VERSION 5.7 ;
NOWIREEXTENSIONATPIN ON ;
DIVIDERCHAR "/" ;
BUSBITCHARS "[]" ;

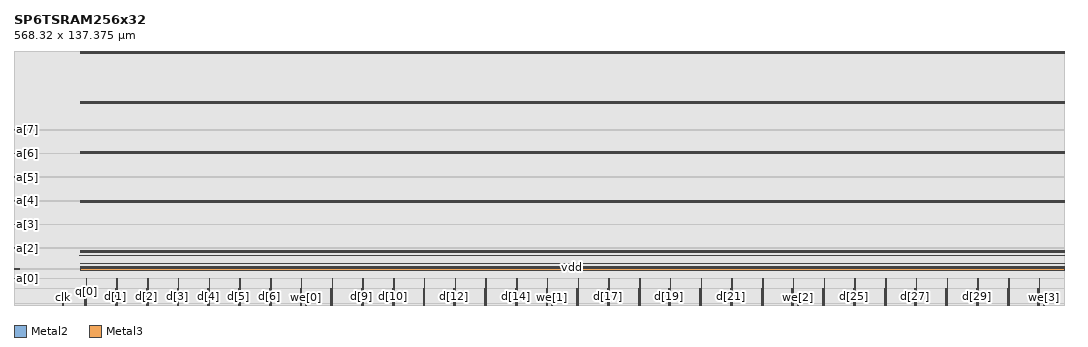
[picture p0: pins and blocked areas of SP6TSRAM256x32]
MACRO SP6TSRAM256x32
  CLASS BLOCK ;
  FOREIGN SP6TSRAM256x32 ;
  ORIGIN 0.000 0.000 ;
  SIZE 568.320 BY 137.375 ;
  SYMMETRY X Y R90 ;
  PIN clk
    USE CLOCK ;
    DIRECTION INPUT ;
    PORT
      LAYER Metal2 ;
        RECT 26.175 0.000 26.555 1.900 ;
    END
  END clk
  PIN a[0]
    USE SIGNAL ;
    DIRECTION INPUT ;
    PORT
      LAYER Metal3 ;
        RECT 0.000 14.185 2.980 14.465 ;
    END
  END a[0]
  PIN a[1]
    USE SIGNAL ;
    DIRECTION INPUT ;
    PORT
      LAYER Metal3 ;
        RECT 0.000 19.485 2.980 19.765 ;
    END
  END a[1]
  PIN a[2]
    USE SIGNAL ;
    DIRECTION INPUT ;
    PORT
      LAYER Metal3 ;
        RECT 0.000 30.685 2.510 30.965 ;
    END
  END a[2]
  PIN a[3]
    USE SIGNAL ;
    DIRECTION INPUT ;
    PORT
      LAYER Metal3 ;
        RECT 0.000 43.485 2.510 43.765 ;
    END
  END a[3]
  PIN a[4]
    USE SIGNAL ;
    DIRECTION INPUT ;
    PORT
      LAYER Metal3 ;
        RECT 0.000 56.285 2.510 56.565 ;
    END
  END a[4]
  PIN a[5]
    USE SIGNAL ;
    DIRECTION INPUT ;
    PORT
      LAYER Metal3 ;
        RECT 0.000 69.085 2.510 69.365 ;
    END
  END a[5]
  PIN a[6]
    USE SIGNAL ;
    DIRECTION INPUT ;
    PORT
      LAYER Metal3 ;
        RECT 0.000 81.885 2.510 82.165 ;
    END
  END a[6]
  PIN a[7]
    USE SIGNAL ;
    DIRECTION INPUT ;
    PORT
      LAYER Metal3 ;
        RECT 0.000 94.685 2.510 94.965 ;
    END
  END a[7]
  PIN d[0]
    USE SIGNAL ;
    DIRECTION INPUT ;
    PORT
      LAYER Metal3 ;
        RECT 38.350 0.000 38.630 9.140 ;
    END
  END d[0]
  PIN d[1]
    USE SIGNAL ;
    DIRECTION INPUT ;
    PORT
      LAYER Metal3 ;
        RECT 54.990 0.000 55.270 9.140 ;
    END
  END d[1]
  PIN d[2]
    USE SIGNAL ;
    DIRECTION INPUT ;
    PORT
      LAYER Metal3 ;
        RECT 71.630 0.000 71.910 9.140 ;
    END
  END d[2]
  PIN d[3]
    USE SIGNAL ;
    DIRECTION INPUT ;
    PORT
      LAYER Metal3 ;
        RECT 88.270 0.000 88.550 9.140 ;
    END
  END d[3]
  PIN d[4]
    USE SIGNAL ;
    DIRECTION INPUT ;
    PORT
      LAYER Metal3 ;
        RECT 104.910 0.000 105.190 9.140 ;
    END
  END d[4]
  PIN d[5]
    USE SIGNAL ;
    DIRECTION INPUT ;
    PORT
      LAYER Metal3 ;
        RECT 121.550 0.000 121.830 9.140 ;
    END
  END d[5]
  PIN d[6]
    USE SIGNAL ;
    DIRECTION INPUT ;
    PORT
      LAYER Metal3 ;
        RECT 138.190 0.000 138.470 9.140 ;
    END
  END d[6]
  PIN d[7]
    USE SIGNAL ;
    DIRECTION INPUT ;
    PORT
      LAYER Metal3 ;
        RECT 154.830 0.000 155.110 9.140 ;
    END
  END d[7]
  PIN d[8]
    USE SIGNAL ;
    DIRECTION INPUT ;
    PORT
      LAYER Metal3 ;
        RECT 171.470 0.000 171.750 9.140 ;
    END
  END d[8]
  PIN d[9]
    USE SIGNAL ;
    DIRECTION INPUT ;
    PORT
      LAYER Metal3 ;
        RECT 188.110 0.000 188.390 9.140 ;
    END
  END d[9]
  PIN d[10]
    USE SIGNAL ;
    DIRECTION INPUT ;
    PORT
      LAYER Metal3 ;
        RECT 204.750 0.000 205.030 9.140 ;
    END
  END d[10]
  PIN d[11]
    USE SIGNAL ;
    DIRECTION INPUT ;
    PORT
      LAYER Metal3 ;
        RECT 221.390 0.000 221.670 9.140 ;
    END
  END d[11]
  PIN d[12]
    USE SIGNAL ;
    DIRECTION INPUT ;
    PORT
      LAYER Metal3 ;
        RECT 238.030 0.000 238.310 9.140 ;
    END
  END d[12]
  PIN d[13]
    USE SIGNAL ;
    DIRECTION INPUT ;
    PORT
      LAYER Metal3 ;
        RECT 254.670 0.000 254.950 9.140 ;
    END
  END d[13]
  PIN d[14]
    USE SIGNAL ;
    DIRECTION INPUT ;
    PORT
      LAYER Metal3 ;
        RECT 271.310 0.000 271.590 9.140 ;
    END
  END d[14]
  PIN d[15]
    USE SIGNAL ;
    DIRECTION INPUT ;
    PORT
      LAYER Metal3 ;
        RECT 287.950 0.000 288.230 9.140 ;
    END
  END d[15]
  PIN d[16]
    USE SIGNAL ;
    DIRECTION INPUT ;
    PORT
      LAYER Metal3 ;
        RECT 304.590 0.000 304.870 9.140 ;
    END
  END d[16]
  PIN d[17]
    USE SIGNAL ;
    DIRECTION INPUT ;
    PORT
      LAYER Metal3 ;
        RECT 321.230 0.000 321.510 9.140 ;
    END
  END d[17]
  PIN d[18]
    USE SIGNAL ;
    DIRECTION INPUT ;
    PORT
      LAYER Metal3 ;
        RECT 337.870 0.000 338.150 9.140 ;
    END
  END d[18]
  PIN d[19]
    USE SIGNAL ;
    DIRECTION INPUT ;
    PORT
      LAYER Metal3 ;
        RECT 354.510 0.000 354.790 9.140 ;
    END
  END d[19]
  PIN d[20]
    USE SIGNAL ;
    DIRECTION INPUT ;
    PORT
      LAYER Metal3 ;
        RECT 371.150 0.000 371.430 9.140 ;
    END
  END d[20]
  PIN d[21]
    USE SIGNAL ;
    DIRECTION INPUT ;
    PORT
      LAYER Metal3 ;
        RECT 387.790 0.000 388.070 9.140 ;
    END
  END d[21]
  PIN d[22]
    USE SIGNAL ;
    DIRECTION INPUT ;
    PORT
      LAYER Metal3 ;
        RECT 404.430 0.000 404.710 9.140 ;
    END
  END d[22]
  PIN d[23]
    USE SIGNAL ;
    DIRECTION INPUT ;
    PORT
      LAYER Metal3 ;
        RECT 421.070 0.000 421.350 9.140 ;
    END
  END d[23]
  PIN d[24]
    USE SIGNAL ;
    DIRECTION INPUT ;
    PORT
      LAYER Metal3 ;
        RECT 437.710 0.000 437.990 9.140 ;
    END
  END d[24]
  PIN d[25]
    USE SIGNAL ;
    DIRECTION INPUT ;
    PORT
      LAYER Metal3 ;
        RECT 454.350 0.000 454.630 9.140 ;
    END
  END d[25]
  PIN d[26]
    USE SIGNAL ;
    DIRECTION INPUT ;
    PORT
      LAYER Metal3 ;
        RECT 470.990 0.000 471.270 9.140 ;
    END
  END d[26]
  PIN d[27]
    USE SIGNAL ;
    DIRECTION INPUT ;
    PORT
      LAYER Metal3 ;
        RECT 487.630 0.000 487.910 9.140 ;
    END
  END d[27]
  PIN d[28]
    USE SIGNAL ;
    DIRECTION INPUT ;
    PORT
      LAYER Metal3 ;
        RECT 504.270 0.000 504.550 9.140 ;
    END
  END d[28]
  PIN d[29]
    USE SIGNAL ;
    DIRECTION INPUT ;
    PORT
      LAYER Metal3 ;
        RECT 520.910 0.000 521.190 9.140 ;
    END
  END d[29]
  PIN d[30]
    USE SIGNAL ;
    DIRECTION INPUT ;
    PORT
      LAYER Metal3 ;
        RECT 537.550 0.000 537.830 9.140 ;
    END
  END d[30]
  PIN d[31]
    USE SIGNAL ;
    DIRECTION INPUT ;
    PORT
      LAYER Metal3 ;
        RECT 554.190 0.000 554.470 9.140 ;
    END
  END d[31]
  PIN we[0]
    USE SIGNAL ;
    DIRECTION INPUT ;
    PORT
      LAYER Metal3 ;
        RECT 157.870 0.000 158.150 1.000 ;
    END
  END we[0]
  PIN we[1]
    USE SIGNAL ;
    DIRECTION INPUT ;
    PORT
      LAYER Metal3 ;
        RECT 290.990 0.000 291.270 1.000 ;
    END
  END we[1]
  PIN we[2]
    USE SIGNAL ;
    DIRECTION INPUT ;
    PORT
      LAYER Metal3 ;
        RECT 424.110 0.000 424.390 1.000 ;
    END
  END we[2]
  PIN we[3]
    USE SIGNAL ;
    DIRECTION INPUT ;
    PORT
      LAYER Metal3 ;
        RECT 557.230 0.000 557.510 1.000 ;
    END
  END we[3]
  PIN q[0]
    USE SIGNAL ;
    DIRECTION OUTPUT ;
    PORT
      LAYER Metal3 ;
        RECT 39.090 0.000 39.370 14.190 ;
    END
  END q[0]
  PIN q[1]
    USE SIGNAL ;
    DIRECTION OUTPUT ;
    PORT
      LAYER Metal3 ;
        RECT 55.730 0.000 56.010 14.190 ;
    END
  END q[1]
  PIN q[2]
    USE SIGNAL ;
    DIRECTION OUTPUT ;
    PORT
      LAYER Metal3 ;
        RECT 72.370 0.000 72.650 14.190 ;
    END
  END q[2]
  PIN q[3]
    USE SIGNAL ;
    DIRECTION OUTPUT ;
    PORT
      LAYER Metal3 ;
        RECT 89.010 0.000 89.290 14.190 ;
    END
  END q[3]
  PIN q[4]
    USE SIGNAL ;
    DIRECTION OUTPUT ;
    PORT
      LAYER Metal3 ;
        RECT 105.650 0.000 105.930 14.190 ;
    END
  END q[4]
  PIN q[5]
    USE SIGNAL ;
    DIRECTION OUTPUT ;
    PORT
      LAYER Metal3 ;
        RECT 122.290 0.000 122.570 14.190 ;
    END
  END q[5]
  PIN q[6]
    USE SIGNAL ;
    DIRECTION OUTPUT ;
    PORT
      LAYER Metal3 ;
        RECT 138.930 0.000 139.210 14.190 ;
    END
  END q[6]
  PIN q[7]
    USE SIGNAL ;
    DIRECTION OUTPUT ;
    PORT
      LAYER Metal3 ;
        RECT 155.570 0.000 155.850 14.190 ;
    END
  END q[7]
  PIN q[8]
    USE SIGNAL ;
    DIRECTION OUTPUT ;
    PORT
      LAYER Metal3 ;
        RECT 172.210 0.000 172.490 14.190 ;
    END
  END q[8]
  PIN q[9]
    USE SIGNAL ;
    DIRECTION OUTPUT ;
    PORT
      LAYER Metal3 ;
        RECT 188.850 0.000 189.130 14.190 ;
    END
  END q[9]
  PIN q[10]
    USE SIGNAL ;
    DIRECTION OUTPUT ;
    PORT
      LAYER Metal3 ;
        RECT 205.490 0.000 205.770 14.190 ;
    END
  END q[10]
  PIN q[11]
    USE SIGNAL ;
    DIRECTION OUTPUT ;
    PORT
      LAYER Metal3 ;
        RECT 222.130 0.000 222.410 14.190 ;
    END
  END q[11]
  PIN q[12]
    USE SIGNAL ;
    DIRECTION OUTPUT ;
    PORT
      LAYER Metal3 ;
        RECT 238.770 0.000 239.050 14.190 ;
    END
  END q[12]
  PIN q[13]
    USE SIGNAL ;
    DIRECTION OUTPUT ;
    PORT
      LAYER Metal3 ;
        RECT 255.410 0.000 255.690 14.190 ;
    END
  END q[13]
  PIN q[14]
    USE SIGNAL ;
    DIRECTION OUTPUT ;
    PORT
      LAYER Metal3 ;
        RECT 272.050 0.000 272.330 14.190 ;
    END
  END q[14]
  PIN q[15]
    USE SIGNAL ;
    DIRECTION OUTPUT ;
    PORT
      LAYER Metal3 ;
        RECT 288.690 0.000 288.970 14.190 ;
    END
  END q[15]
  PIN q[16]
    USE SIGNAL ;
    DIRECTION OUTPUT ;
    PORT
      LAYER Metal3 ;
        RECT 305.330 0.000 305.610 14.190 ;
    END
  END q[16]
  PIN q[17]
    USE SIGNAL ;
    DIRECTION OUTPUT ;
    PORT
      LAYER Metal3 ;
        RECT 321.970 0.000 322.250 14.190 ;
    END
  END q[17]
  PIN q[18]
    USE SIGNAL ;
    DIRECTION OUTPUT ;
    PORT
      LAYER Metal3 ;
        RECT 338.610 0.000 338.890 14.190 ;
    END
  END q[18]
  PIN q[19]
    USE SIGNAL ;
    DIRECTION OUTPUT ;
    PORT
      LAYER Metal3 ;
        RECT 355.250 0.000 355.530 14.190 ;
    END
  END q[19]
  PIN q[20]
    USE SIGNAL ;
    DIRECTION OUTPUT ;
    PORT
      LAYER Metal3 ;
        RECT 371.890 0.000 372.170 14.190 ;
    END
  END q[20]
  PIN q[21]
    USE SIGNAL ;
    DIRECTION OUTPUT ;
    PORT
      LAYER Metal3 ;
        RECT 388.530 0.000 388.810 14.190 ;
    END
  END q[21]
  PIN q[22]
    USE SIGNAL ;
    DIRECTION OUTPUT ;
    PORT
      LAYER Metal3 ;
        RECT 405.170 0.000 405.450 14.190 ;
    END
  END q[22]
  PIN q[23]
    USE SIGNAL ;
    DIRECTION OUTPUT ;
    PORT
      LAYER Metal3 ;
        RECT 421.810 0.000 422.090 14.190 ;
    END
  END q[23]
  PIN q[24]
    USE SIGNAL ;
    DIRECTION OUTPUT ;
    PORT
      LAYER Metal3 ;
        RECT 438.450 0.000 438.730 14.190 ;
    END
  END q[24]
  PIN q[25]
    USE SIGNAL ;
    DIRECTION OUTPUT ;
    PORT
      LAYER Metal3 ;
        RECT 455.090 0.000 455.370 14.190 ;
    END
  END q[25]
  PIN q[26]
    USE SIGNAL ;
    DIRECTION OUTPUT ;
    PORT
      LAYER Metal3 ;
        RECT 471.730 0.000 472.010 14.190 ;
    END
  END q[26]
  PIN q[27]
    USE SIGNAL ;
    DIRECTION OUTPUT ;
    PORT
      LAYER Metal3 ;
        RECT 488.370 0.000 488.650 14.190 ;
    END
  END q[27]
  PIN q[28]
    USE SIGNAL ;
    DIRECTION OUTPUT ;
    PORT
      LAYER Metal3 ;
        RECT 505.010 0.000 505.290 14.190 ;
    END
  END q[28]
  PIN q[29]
    USE SIGNAL ;
    DIRECTION OUTPUT ;
    PORT
      LAYER Metal3 ;
        RECT 521.650 0.000 521.930 14.190 ;
    END
  END q[29]
  PIN q[30]
    USE SIGNAL ;
    DIRECTION OUTPUT ;
    PORT
      LAYER Metal3 ;
        RECT 538.290 0.000 538.570 14.190 ;
    END
  END q[30]
  PIN q[31]
    USE SIGNAL ;
    DIRECTION OUTPUT ;
    PORT
      LAYER Metal3 ;
        RECT 554.930 0.000 555.210 14.190 ;
    END
  END q[31]
  PIN vss
    USE GROUND ;
    DIRECTION INOUT ;
    PORT
      LAYER Metal3 ;
        RECT 35.840 28.315 568.320 28.715 ;
    END
    PORT
      LAYER Metal3 ;
        RECT 35.840 109.195 568.320 109.595 ;
    END
    PORT
      LAYER Metal3 ;
        RECT 35.840 82.235 568.320 82.635 ;
    END
    PORT
      LAYER Metal3 ;
        RECT 35.840 55.275 568.320 55.675 ;
    END
    PORT
      LAYER Metal3 ;
        RECT 35.840 136.155 568.320 136.555 ;
    END
    PORT
      LAYER Metal3 ;
        RECT 35.840 22.450 568.320 22.730 ;
    END
    PORT
      LAYER Metal3 ;
        RECT 35.840 18.780 568.320 19.780 ;
    END
  END vss
  PIN vdd
    USE POWER ;
    DIRECTION INOUT ;
    PORT
      LAYER Metal3 ;
        RECT 35.840 82.915 568.320 83.315 ;
    END
    PORT
      LAYER Metal3 ;
        RECT 35.840 109.875 568.320 110.275 ;
    END
    PORT
      LAYER Metal3 ;
        RECT 35.840 136.835 568.320 137.235 ;
    END
    PORT
      LAYER Metal3 ;
        RECT 35.840 28.995 568.320 29.395 ;
    END
    PORT
      LAYER Metal3 ;
        RECT 35.840 55.955 568.320 56.355 ;
    END
    PORT
      LAYER Metal3 ;
        RECT 35.840 20.060 568.320 21.060 ;
    END
    PORT
      LAYER Metal3 ;
        RECT 35.650 26.745 568.320 27.025 ;
    END
  END vdd
  OBS
    LAYER Metal1 ;
      RECT 0.000 0.000 568.320 137.375 ;
    LAYER Metal2 ;
      RECT 0.000 0.000 26.175 1.900 ;
      RECT 26.555 0.000 568.320 1.900 ;
      RECT 0.000 1.900 568.320 137.375 ;
    LAYER Metal3 ;
      RECT 0.000 0.000 38.350 1.000 ;
      RECT 38.630 0.000 39.090 1.000 ;
      RECT 39.370 0.000 54.990 1.000 ;
      RECT 55.270 0.000 55.730 1.000 ;
      RECT 56.010 0.000 71.630 1.000 ;
      RECT 71.910 0.000 72.370 1.000 ;
      RECT 72.650 0.000 88.270 1.000 ;
      RECT 88.550 0.000 89.010 1.000 ;
      RECT 89.290 0.000 104.910 1.000 ;
      RECT 105.190 0.000 105.650 1.000 ;
      RECT 105.930 0.000 121.550 1.000 ;
      RECT 121.830 0.000 122.290 1.000 ;
      RECT 122.570 0.000 138.190 1.000 ;
      RECT 138.470 0.000 138.930 1.000 ;
      RECT 139.210 0.000 154.830 1.000 ;
      RECT 155.110 0.000 155.570 1.000 ;
      RECT 155.850 0.000 157.870 1.000 ;
      RECT 158.150 0.000 171.470 1.000 ;
      RECT 171.750 0.000 172.210 1.000 ;
      RECT 172.490 0.000 188.110 1.000 ;
      RECT 188.390 0.000 188.850 1.000 ;
      RECT 189.130 0.000 204.750 1.000 ;
      RECT 205.030 0.000 205.490 1.000 ;
      RECT 205.770 0.000 221.390 1.000 ;
      RECT 221.670 0.000 222.130 1.000 ;
      RECT 222.410 0.000 238.030 1.000 ;
      RECT 238.310 0.000 238.770 1.000 ;
      RECT 239.050 0.000 254.670 1.000 ;
      RECT 254.950 0.000 255.410 1.000 ;
      RECT 255.690 0.000 271.310 1.000 ;
      RECT 271.590 0.000 272.050 1.000 ;
      RECT 272.330 0.000 287.950 1.000 ;
      RECT 288.230 0.000 288.690 1.000 ;
      RECT 288.970 0.000 290.990 1.000 ;
      RECT 291.270 0.000 304.590 1.000 ;
      RECT 304.870 0.000 305.330 1.000 ;
      RECT 305.610 0.000 321.230 1.000 ;
      RECT 321.510 0.000 321.970 1.000 ;
      RECT 322.250 0.000 337.870 1.000 ;
      RECT 338.150 0.000 338.610 1.000 ;
      RECT 338.890 0.000 354.510 1.000 ;
      RECT 354.790 0.000 355.250 1.000 ;
      RECT 355.530 0.000 371.150 1.000 ;
      RECT 371.430 0.000 371.890 1.000 ;
      RECT 372.170 0.000 387.790 1.000 ;
      RECT 388.070 0.000 388.530 1.000 ;
      RECT 388.810 0.000 404.430 1.000 ;
      RECT 404.710 0.000 405.170 1.000 ;
      RECT 405.450 0.000 421.070 1.000 ;
      RECT 421.350 0.000 421.810 1.000 ;
      RECT 422.090 0.000 424.110 1.000 ;
      RECT 424.390 0.000 437.710 1.000 ;
      RECT 437.990 0.000 438.450 1.000 ;
      RECT 438.730 0.000 454.350 1.000 ;
      RECT 454.630 0.000 455.090 1.000 ;
      RECT 455.370 0.000 470.990 1.000 ;
      RECT 471.270 0.000 471.730 1.000 ;
      RECT 472.010 0.000 487.630 1.000 ;
      RECT 487.910 0.000 488.370 1.000 ;
      RECT 488.650 0.000 504.270 1.000 ;
      RECT 504.550 0.000 505.010 1.000 ;
      RECT 505.290 0.000 520.910 1.000 ;
      RECT 521.190 0.000 521.650 1.000 ;
      RECT 521.930 0.000 537.550 1.000 ;
      RECT 537.830 0.000 538.290 1.000 ;
      RECT 538.570 0.000 554.190 1.000 ;
      RECT 554.470 0.000 554.930 1.000 ;
      RECT 555.210 0.000 557.230 1.000 ;
      RECT 557.510 0.000 568.320 1.000 ;
      RECT 0.000 1.000 38.350 9.140 ;
      RECT 38.630 1.000 39.090 9.140 ;
      RECT 39.370 1.000 54.990 9.140 ;
      RECT 55.270 1.000 55.730 9.140 ;
      RECT 56.010 1.000 71.630 9.140 ;
      RECT 71.910 1.000 72.370 9.140 ;
      RECT 72.650 1.000 88.270 9.140 ;
      RECT 88.550 1.000 89.010 9.140 ;
      RECT 89.290 1.000 104.910 9.140 ;
      RECT 105.190 1.000 105.650 9.140 ;
      RECT 105.930 1.000 121.550 9.140 ;
      RECT 121.830 1.000 122.290 9.140 ;
      RECT 122.570 1.000 138.190 9.140 ;
      RECT 138.470 1.000 138.930 9.140 ;
      RECT 139.210 1.000 154.830 9.140 ;
      RECT 155.110 1.000 155.570 9.140 ;
      RECT 155.850 1.000 171.470 9.140 ;
      RECT 171.750 1.000 172.210 9.140 ;
      RECT 172.490 1.000 188.110 9.140 ;
      RECT 188.390 1.000 188.850 9.140 ;
      RECT 189.130 1.000 204.750 9.140 ;
      RECT 205.030 1.000 205.490 9.140 ;
      RECT 205.770 1.000 221.390 9.140 ;
      RECT 221.670 1.000 222.130 9.140 ;
      RECT 222.410 1.000 238.030 9.140 ;
      RECT 238.310 1.000 238.770 9.140 ;
      RECT 239.050 1.000 254.670 9.140 ;
      RECT 254.950 1.000 255.410 9.140 ;
      RECT 255.690 1.000 271.310 9.140 ;
      RECT 271.590 1.000 272.050 9.140 ;
      RECT 272.330 1.000 287.950 9.140 ;
      RECT 288.230 1.000 288.690 9.140 ;
      RECT 288.970 1.000 304.590 9.140 ;
      RECT 304.870 1.000 305.330 9.140 ;
      RECT 305.610 1.000 321.230 9.140 ;
      RECT 321.510 1.000 321.970 9.140 ;
      RECT 322.250 1.000 337.870 9.140 ;
      RECT 338.150 1.000 338.610 9.140 ;
      RECT 338.890 1.000 354.510 9.140 ;
      RECT 354.790 1.000 355.250 9.140 ;
      RECT 355.530 1.000 371.150 9.140 ;
      RECT 371.430 1.000 371.890 9.140 ;
      RECT 372.170 1.000 387.790 9.140 ;
      RECT 388.070 1.000 388.530 9.140 ;
      RECT 388.810 1.000 404.430 9.140 ;
      RECT 404.710 1.000 405.170 9.140 ;
      RECT 405.450 1.000 421.070 9.140 ;
      RECT 421.350 1.000 421.810 9.140 ;
      RECT 422.090 1.000 437.710 9.140 ;
      RECT 437.990 1.000 438.450 9.140 ;
      RECT 438.730 1.000 454.350 9.140 ;
      RECT 454.630 1.000 455.090 9.140 ;
      RECT 455.370 1.000 470.990 9.140 ;
      RECT 471.270 1.000 471.730 9.140 ;
      RECT 472.010 1.000 487.630 9.140 ;
      RECT 487.910 1.000 488.370 9.140 ;
      RECT 488.650 1.000 504.270 9.140 ;
      RECT 504.550 1.000 505.010 9.140 ;
      RECT 505.290 1.000 520.910 9.140 ;
      RECT 521.190 1.000 521.650 9.140 ;
      RECT 521.930 1.000 537.550 9.140 ;
      RECT 537.830 1.000 538.290 9.140 ;
      RECT 538.570 1.000 554.190 9.140 ;
      RECT 554.470 1.000 554.930 9.140 ;
      RECT 555.210 1.000 568.320 9.140 ;
      RECT 0.000 9.140 39.090 14.185 ;
      RECT 39.370 9.140 55.730 14.185 ;
      RECT 56.010 9.140 72.370 14.185 ;
      RECT 72.650 9.140 89.010 14.185 ;
      RECT 89.290 9.140 105.650 14.185 ;
      RECT 105.930 9.140 122.290 14.185 ;
      RECT 122.570 9.140 138.930 14.185 ;
      RECT 139.210 9.140 155.570 14.185 ;
      RECT 155.850 9.140 172.210 14.185 ;
      RECT 172.490 9.140 188.850 14.185 ;
      RECT 189.130 9.140 205.490 14.185 ;
      RECT 205.770 9.140 222.130 14.185 ;
      RECT 222.410 9.140 238.770 14.185 ;
      RECT 239.050 9.140 255.410 14.185 ;
      RECT 255.690 9.140 272.050 14.185 ;
      RECT 272.330 9.140 288.690 14.185 ;
      RECT 288.970 9.140 305.330 14.185 ;
      RECT 305.610 9.140 321.970 14.185 ;
      RECT 322.250 9.140 338.610 14.185 ;
      RECT 338.890 9.140 355.250 14.185 ;
      RECT 355.530 9.140 371.890 14.185 ;
      RECT 372.170 9.140 388.530 14.185 ;
      RECT 388.810 9.140 405.170 14.185 ;
      RECT 405.450 9.140 421.810 14.185 ;
      RECT 422.090 9.140 438.450 14.185 ;
      RECT 438.730 9.140 455.090 14.185 ;
      RECT 455.370 9.140 471.730 14.185 ;
      RECT 472.010 9.140 488.370 14.185 ;
      RECT 488.650 9.140 505.010 14.185 ;
      RECT 505.290 9.140 521.650 14.185 ;
      RECT 521.930 9.140 538.290 14.185 ;
      RECT 538.570 9.140 554.930 14.185 ;
      RECT 555.210 9.140 568.320 14.185 ;
      RECT 2.980 14.185 39.090 14.190 ;
      RECT 39.370 14.185 55.730 14.190 ;
      RECT 56.010 14.185 72.370 14.190 ;
      RECT 72.650 14.185 89.010 14.190 ;
      RECT 89.290 14.185 105.650 14.190 ;
      RECT 105.930 14.185 122.290 14.190 ;
      RECT 122.570 14.185 138.930 14.190 ;
      RECT 139.210 14.185 155.570 14.190 ;
      RECT 155.850 14.185 172.210 14.190 ;
      RECT 172.490 14.185 188.850 14.190 ;
      RECT 189.130 14.185 205.490 14.190 ;
      RECT 205.770 14.185 222.130 14.190 ;
      RECT 222.410 14.185 238.770 14.190 ;
      RECT 239.050 14.185 255.410 14.190 ;
      RECT 255.690 14.185 272.050 14.190 ;
      RECT 272.330 14.185 288.690 14.190 ;
      RECT 288.970 14.185 305.330 14.190 ;
      RECT 305.610 14.185 321.970 14.190 ;
      RECT 322.250 14.185 338.610 14.190 ;
      RECT 338.890 14.185 355.250 14.190 ;
      RECT 355.530 14.185 371.890 14.190 ;
      RECT 372.170 14.185 388.530 14.190 ;
      RECT 388.810 14.185 405.170 14.190 ;
      RECT 405.450 14.185 421.810 14.190 ;
      RECT 422.090 14.185 438.450 14.190 ;
      RECT 438.730 14.185 455.090 14.190 ;
      RECT 455.370 14.185 471.730 14.190 ;
      RECT 472.010 14.185 488.370 14.190 ;
      RECT 488.650 14.185 505.010 14.190 ;
      RECT 505.290 14.185 521.650 14.190 ;
      RECT 521.930 14.185 538.290 14.190 ;
      RECT 538.570 14.185 554.930 14.190 ;
      RECT 555.210 14.185 568.320 14.190 ;
      RECT 2.980 14.190 568.320 14.465 ;
      RECT 0.000 14.465 568.320 19.485 ;
      RECT 2.980 19.485 568.320 19.765 ;
      RECT 0.000 19.765 568.320 30.685 ;
      RECT 2.510 30.685 568.320 30.965 ;
      RECT 0.000 30.965 568.320 43.485 ;
      RECT 2.510 43.485 568.320 43.765 ;
      RECT 0.000 43.765 568.320 56.285 ;
      RECT 2.510 56.285 568.320 56.565 ;
      RECT 0.000 56.565 568.320 69.085 ;
      RECT 2.510 69.085 568.320 69.365 ;
      RECT 0.000 69.365 568.320 81.885 ;
      RECT 2.510 81.885 568.320 82.165 ;
      RECT 0.000 82.165 568.320 94.685 ;
      RECT 2.510 94.685 568.320 94.965 ;
      RECT 0.000 94.965 568.320 137.375 ;
  END
END SP6TSRAM256x32
